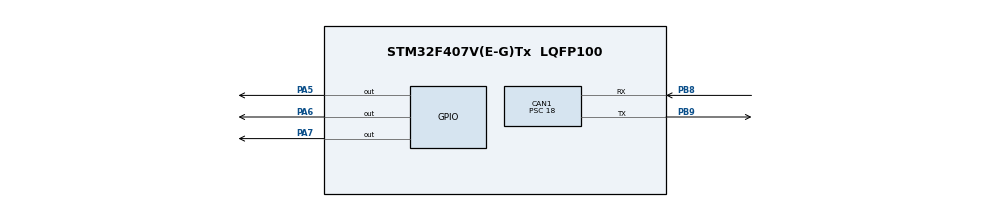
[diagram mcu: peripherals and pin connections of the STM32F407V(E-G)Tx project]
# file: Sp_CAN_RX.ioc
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CAN1.BS2=CAN_BS2_2TQ
CAN1.CalculateBaudRate=500000
CAN1.CalculateTimeBit=2000
CAN1.CalculateTimeQuantum=500.0
CAN1.Prescaler=18
Mcu.Family=STM32F4
Mcu.Name=STM32F407V(E-G)Tx
Mcu.Package=LQFP100
NVIC.PriorityGroup=NVIC_PRIORITYGROUP_0
NVIC.RCC_IRQn=true\:0\:0\:false\:false\:true\:true\:false\:true
PA5.GPIO_Speed=GPIO_SPEED_FREQ_MEDIUM
PA5.Signal=GPIO_Output
PA6.GPIO_Speed=GPIO_SPEED_FREQ_MEDIUM
PA6.Signal=GPIO_Output
PA7.GPIO_Speed=GPIO_SPEED_FREQ_MEDIUM
PA7.Signal=GPIO_Output
PB8.Mode=CAN_Activate
PB8.Signal=CAN1_RX
PB9.Mode=CAN_Activate
PB9.Signal=CAN1_TX
PH0-OSC_IN.Mode=HSE-External-Oscillator
PH0-OSC_IN.Signal=RCC_OSC_IN
PH1-OSC_OUT.Mode=HSE-External-Oscillator
PH1-OSC_OUT.Signal=RCC_OSC_OUT
ProjectManager.HeapSize=0x200
ProjectManager.StackSize=0x400
ProjectManager.TargetToolchain=STM32CubeIDE
RCC.48MHZClocksFreq_Value=20571428.57142857
RCC.AHBFreq_Value=72000000
RCC.APB1CLKDivider=RCC_HCLK_DIV2
RCC.APB1Freq_Value=36000000
RCC.APB1TimFreq_Value=72000000
RCC.APB2CLKDivider=RCC_HCLK_DIV2
RCC.APB2Freq_Value=36000000
RCC.APB2TimFreq_Value=72000000
RCC.CortexFreq_Value=72000000
RCC.HCLKFreq_Value=72000000
RCC.HSE_VALUE=8000000
RCC.HSI_VALUE=16000000
RCC.LSE_VALUE=32768
RCC.PLLM=4
RCC.PLLN=72
RCC.PLLQ=7
RCC.PLLSourceVirtual=RCC_PLLSOURCE_HSE
RCC.SYSCLKFreq_VALUE=72000000
RCC.SYSCLKSource=RCC_SYSCLKSOURCE_PLLCLK
RCC.VCOOutputFreq_Value=144000000
board=STM32F407G-DISC1

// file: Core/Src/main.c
/* USER CODE BEGIN Header */
/**
  ******************************************************************************
  * @file           : main.c
  * @brief          : Main program body
  ******************************************************************************
  * @attention
  *
  * Copyright (c) 2023 STMicroelectronics.
  * All rights reserved.
  *
  * This software is licensed under terms that can be found in the LICENSE file
  * in the root directory of this software component.
  * If no LICENSE file comes with this software, it is provided AS-IS.
  ******************************************************************************
  */
/* USER CODE END Header */
#include "main.h"

/* USER CODE BEGIN Includes */
#include <string.h>
#include <stdlib.h>
/* USER CODE END Includes */

/* USER CODE BEGIN PD */
#define SPEED_LIMIT 40  // Speed limit in km/h
/* USER CODE END PD */

CAN_HandleTypeDef hcan1;
CAN_TxHeaderTypeDef TxHeader;
CAN_RxHeaderTypeDef RxHeader;
uint8_t TxData[8];
uint8_t RxData[8];

void SystemClock_Config(void);
static void MX_GPIO_Init(void);
static void MX_CAN1_Init(void);
void CheckSpeed(int speed);
void ActivateBuzzer(void);

/* USER CODE BEGIN 0 */

void CheckSpeed(int speed) {
    if (speed > SPEED_LIMIT) {
        HAL_GPIO_WritePin(GPIOA, GPIO_PIN_6, GPIO_PIN_SET); // Red LED ON
        HAL_GPIO_WritePin(GPIOA, GPIO_PIN_7, GPIO_PIN_RESET); // Green LED OFF
        ActivateBuzzer();
    } else {
        HAL_GPIO_WritePin(GPIOA, GPIO_PIN_6, GPIO_PIN_RESET); // Red LED OFF
        HAL_GPIO_WritePin(GPIOA, GPIO_PIN_7, GPIO_PIN_SET); // Green LED ON
    }
}

void ActivateBuzzer(void) {
    for (int i = 0; i < 2; i++) {
        HAL_GPIO_WritePin(GPIOA, GPIO_PIN_5, GPIO_PIN_SET); // Buzzer ON
        HAL_Delay(5000); // 5 seconds
        HAL_GPIO_WritePin(GPIOA, GPIO_PIN_5, GPIO_PIN_RESET); // Buzzer OFF
        HAL_Delay(1000); // 1 second pause
    }
}

void CAN_ReceiveData(void) {
    // Receive CAN message
    if (HAL_CAN_GetRxMessage(&hcan1, CAN_RX_FIFO0, &RxHeader, RxData) == HAL_OK) {
        int speed = *((int*)RxData);  // Assuming speed is sent as an integer
        CheckSpeed(speed);
    }
}

void HAL_CAN_RxFifo0MsgPendingCallback(CAN_HandleTypeDef *hcan) {
    CAN_ReceiveData();  // Call function when a new CAN message is available
}

/* USER CODE END 0 */

int main(void)
{

  /* MCU Configuration--------------------------------------------------------*/
  HAL_Init();

  /* Configure the system clock */
  SystemClock_Config();

  /* Initialize all configured peripherals */
  MX_GPIO_Init();
  MX_CAN1_Init();  // Initialize CAN

  /* USER CODE BEGIN 2 */
  // Optionally, transmit a message to indicate readiness over CAN (or debug with UART)
  /* USER CODE END 2 */

  /* Infinite loop */
  while (1)
  {
    /* USER CODE BEGIN WHILE */
    // CAN receive is handled by the interrupt callback, no need for a polling loop
    /* USER CODE END WHILE */
  }
  /* USER CODE END 3 */
}

void SystemClock_Config(void)
{
    RCC_OscInitTypeDef RCC_OscInitStruct = {0};
    RCC_ClkInitTypeDef RCC_ClkInitStruct = {0};

    __HAL_RCC_PWR_CLK_ENABLE();
    __HAL_PWR_VOLTAGESCALING_CONFIG(PWR_REGULATOR_VOLTAGE_SCALE1);

    RCC_OscInitStruct.OscillatorType = RCC_OSCILLATORTYPE_HSE;
    RCC_OscInitStruct.HSEState = RCC_HSE_ON;
    RCC_OscInitStruct.PLL.PLLState = RCC_PLL_ON;
    RCC_OscInitStruct.PLL.PLLSource = RCC_PLLSOURCE_HSE;
    RCC_OscInitStruct.PLL.PLLM = 8;
    RCC_OscInitStruct.PLL.PLLN = 336;
    RCC_OscInitStruct.PLL.PLLP = RCC_PLLP_DIV2;
    RCC_OscInitStruct.PLL.PLLQ = 7;
    if (HAL_RCC_OscConfig(&RCC_OscInitStruct) != HAL_OK)
    {
        Error_Handler();
    }

    RCC_ClkInitStruct.ClockType = (RCC_CLOCKTYPE_HCLK | RCC_CLOCKTYPE_SYSCLK |
                                   RCC_CLOCKTYPE_PCLK1 | RCC_CLOCKTYPE_PCLK2);
    RCC_ClkInitStruct.SYSCLKSource = RCC_SYSCLKSOURCE_PLLCLK;
    RCC_ClkInitStruct.AHBCLKDivider = RCC_SYSCLK_DIV1;
    RCC_ClkInitStruct.APB1CLKDivider = RCC_HCLK_DIV4;
    RCC_ClkInitStruct.APB2CLKDivider = RCC_HCLK_DIV2;
    if (HAL_RCC_ClockConfig(&RCC_ClkInitStruct, FLASH_LATENCY_5) != HAL_OK)
    {
        Error_Handler();
    }
}

static void MX_GPIO_Init(void)
{
  /* GPIO Ports Clock Enable */
  __HAL_RCC_GPIOA_CLK_ENABLE();

  GPIO_InitTypeDef GPIO_InitStruct = {0};

  /* Configure GPIO pins for LEDs and Buzzer */
  GPIO_InitStruct.Pin = GPIO_PIN_5 | GPIO_PIN_6 | GPIO_PIN_7;
  GPIO_InitStruct.Mode = GPIO_MODE_OUTPUT_PP;
  GPIO_InitStruct.Pull = GPIO_NOPULL;
  GPIO_InitStruct.Speed = GPIO_SPEED_FREQ_LOW;
  HAL_GPIO_Init(GPIOA, &GPIO_InitStruct);
}

static void MX_CAN1_Init(void)
{
    hcan1.Instance = CAN1;
    hcan1.Init.Prescaler = 16;
    hcan1.Init.Mode = CAN_MODE_NORMAL;
    hcan1.Init.SyncJumpWidth = CAN_SJW_1TQ;
    hcan1.Init.TimeSeg1 = CAN_BS1_1TQ;
    hcan1.Init.TimeSeg2 = CAN_BS2_1TQ;
    hcan1.Init.AutoBusOff = DISABLE;
    hcan1.Init.AutoWakeUp = DISABLE;
    hcan1.Init.AutoRetransmission = DISABLE;
    hcan1.Init.ReceiveFifoLocked = DISABLE;
    hcan1.Init.TransmitFifoPriority = DISABLE;
    if (HAL_CAN_Init(&hcan1) != HAL_OK)
    {
        Error_Handler();
    }

    // Configure the filter
    CAN_FilterTypeDef canFilter;
    canFilter.FilterBank = 0;
    canFilter.FilterMode = CAN_FILTERMODE_IDMASK;
    canFilter.FilterScale = CAN_FILTERSCALE_32BIT;
    canFilter.FilterIdHigh = 0;
    canFilter.FilterIdLow = 0;
    canFilter.FilterMaskIdHigh = 0;
    canFilter.FilterMaskIdLow = 0;
    canFilter.FilterFIFOAssignment = CAN_RX_FIFO0;
    canFilter.FilterActivation = ENABLE;
    HAL_CAN_ConfigFilter(&hcan1, &canFilter);

    // Start CAN in receive mode
    if (HAL_CAN_Start(&hcan1) != HAL_OK)
    {
        Error_Handler();
    }

    // Enable interrupt for CAN receive
    HAL_CAN_ActivateNotification(&hcan1, CAN_IT_RX_FIFO0_MSG_PENDING);
}

void Error_Handler(void)
{
  __disable_irq();
  while (1)
  {
  }
}
